VERSION 5.7 ;
  NOWIREEXTENSIONATPIN ON ;
  DIVIDERCHAR "/" ;
  BUSBITCHARS "[]" ;
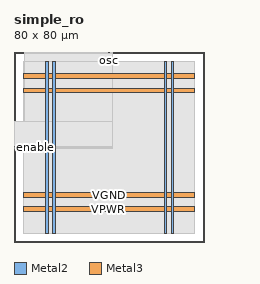
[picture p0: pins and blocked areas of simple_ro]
MACRO simple_ro
  CLASS BLOCK ;
  FOREIGN simple_ro ;
  ORIGIN 0.000 0.000 ;
  SIZE 80.000 BY 80.000 ;
  PIN VGND
    DIRECTION INOUT ;
    USE GROUND ;
    PORT
      LAYER Metal2 ;
        RECT 16.340 3.560 17.340 75.820 ;
    END
    PORT
      LAYER Metal2 ;
        RECT 66.340 3.560 67.340 75.820 ;
    END
    PORT
      LAYER Metal3 ;
        RECT 3.840 18.780 75.840 20.780 ;
    END
    PORT
      LAYER Metal3 ;
        RECT 3.840 68.780 75.840 70.780 ;
    END
  END VGND
  PIN VPWR
    DIRECTION INOUT ;
    USE POWER ;
    PORT
      LAYER Metal2 ;
        RECT 13.340 3.560 14.340 75.820 ;
    END
    PORT
      LAYER Metal2 ;
        RECT 63.340 3.560 64.340 75.820 ;
    END
    PORT
      LAYER Metal3 ;
        RECT 3.840 12.780 75.840 14.780 ;
    END
    PORT
      LAYER Metal3 ;
        RECT 3.840 62.780 75.840 64.780 ;
    END
  END VPWR
  PIN enable
    DIRECTION INPUT ;
    USE SIGNAL ;
    ANTENNAGATEAREA 0.180700 ;
    PORT
      LAYER Metal3 ;
        RECT 0.000 39.700 0.400 40.100 ;
    END
  END enable
  PIN osc
    DIRECTION OUTPUT ;
    USE SIGNAL ;
    ANTENNADIFFAREA 0.708600 ;
    PORT
      LAYER Metal2 ;
        RECT 39.640 79.600 40.040 80.000 ;
    END
  END osc
  OBS
      LAYER GatPoly ;
        RECT 3.840 3.630 75.840 75.750 ;
      LAYER Metal1 ;
        RECT 3.840 3.560 75.840 75.820 ;
      LAYER Metal2 ;
        RECT 4.215 79.390 39.430 79.600 ;
        RECT 40.250 79.390 41.385 79.600 ;
        RECT 4.215 76.030 41.385 79.390 ;
        RECT 4.215 39.335 13.130 76.030 ;
        RECT 14.550 39.335 16.130 76.030 ;
        RECT 17.550 39.335 41.385 76.030 ;
      LAYER Metal3 ;
        RECT 0.400 40.310 41.425 50.920 ;
        RECT 0.610 39.800 41.425 40.310 ;
  END
END simple_ro
END LIBRARY

